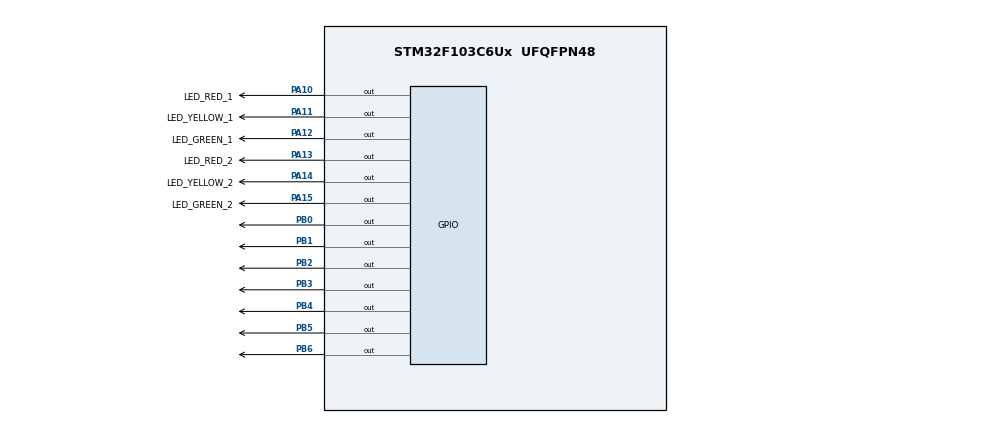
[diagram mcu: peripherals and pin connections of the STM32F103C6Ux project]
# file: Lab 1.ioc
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Mcu.Family=STM32F1
Mcu.Name=STM32F103C6Ux
Mcu.Package=UFQFPN48
NVIC.PriorityGroup=NVIC_PRIORITYGROUP_4
PA10.GPIO_Label=LED_RED_1
PA10.Signal=GPIO_Output
PA11.GPIO_Label=LED_YELLOW_1
PA11.Signal=GPIO_Output
PA12.GPIO_Label=LED_GREEN_1
PA12.Signal=GPIO_Output
PA13.GPIO_Label=LED_RED_2
PA13.Signal=GPIO_Output
PA14.GPIO_Label=LED_YELLOW_2
PA14.Signal=GPIO_Output
PA15.GPIO_Label=LED_GREEN_2
PA15.Signal=GPIO_Output
PB0.Signal=GPIO_Output
PB1.Signal=GPIO_Output
PB2.Signal=GPIO_Output
PB3.Signal=GPIO_Output
PB4.Signal=GPIO_Output
PB5.Signal=GPIO_Output
PB6.Signal=GPIO_Output
ProjectManager.HeapSize=0x200
ProjectManager.StackSize=0x400
ProjectManager.TargetToolchain=STM32CubeIDE
RCC.APB1Freq_Value=8000000
RCC.APB2Freq_Value=8000000
board=custom

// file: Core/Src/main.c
/* USER CODE BEGIN Header */
/**
  ******************************************************************************
  * @file           : main.c
  * @brief          : Main program body
  ******************************************************************************
  * @attention
  *
  * Copyright (c) 2022 STMicroelectronics.
  * All rights reserved.
  *
  * This software is licensed under terms that can be found in the LICENSE file
  * in the root directory of this software component.
  * If no LICENSE file comes with this software, it is provided AS-IS.
  *
  ******************************************************************************
  */
/* USER CODE END Header */
#include "main.h"

void SystemClock_Config(void);
static void MX_GPIO_Init(void);
/* USER CODE BEGIN PFP */
void display_only_LED(int num);
/* USER CODE END PFP */

int main(void)
{

  /* MCU Configuration--------------------------------------------------------*/

  /* Reset of all peripherals, Initializes the Flash interface and the Systick. */
  HAL_Init();

  /* Configure the system clock */
  SystemClock_Config();

  /* Initialize all configured peripherals */
  MX_GPIO_Init();
  /* USER CODE BEGIN 2 */

  int counter = 0;
  /* USER CODE END 2 */

  /* Infinite loop */
  while (1)
  {

    /* USER CODE BEGIN 3 */
	  if( counter >= 12) counter = 0;
	  display_only_LED ( counter ++) ;
	  HAL_Delay (1000) ;
  }
  /* USER CODE END 3 */
}

void SystemClock_Config(void)
{
  RCC_OscInitTypeDef RCC_OscInitStruct = {0};
  RCC_ClkInitTypeDef RCC_ClkInitStruct = {0};

  /** Initializes the RCC Oscillators according to the specified parameters
  * in the RCC_OscInitTypeDef structure.
  */
  RCC_OscInitStruct.OscillatorType = RCC_OSCILLATORTYPE_HSI;
  RCC_OscInitStruct.HSIState = RCC_HSI_ON;
  RCC_OscInitStruct.HSICalibrationValue = RCC_HSICALIBRATION_DEFAULT;
  RCC_OscInitStruct.PLL.PLLState = RCC_PLL_NONE;
  if (HAL_RCC_OscConfig(&RCC_OscInitStruct) != HAL_OK)
  {
    Error_Handler();
  }

  /** Initializes the CPU, AHB and APB buses clocks
  */
  RCC_ClkInitStruct.ClockType = RCC_CLOCKTYPE_HCLK|RCC_CLOCKTYPE_SYSCLK
                              |RCC_CLOCKTYPE_PCLK1|RCC_CLOCKTYPE_PCLK2;
  RCC_ClkInitStruct.SYSCLKSource = RCC_SYSCLKSOURCE_HSI;
  RCC_ClkInitStruct.AHBCLKDivider = RCC_SYSCLK_DIV1;
  RCC_ClkInitStruct.APB1CLKDivider = RCC_HCLK_DIV1;
  RCC_ClkInitStruct.APB2CLKDivider = RCC_HCLK_DIV1;

  if (HAL_RCC_ClockConfig(&RCC_ClkInitStruct, FLASH_LATENCY_0) != HAL_OK)
  {
    Error_Handler();
  }
}

static void MX_GPIO_Init(void)
{
  GPIO_InitTypeDef GPIO_InitStruct = {0};

  /* GPIO Ports Clock Enable */
  __HAL_RCC_GPIOA_CLK_ENABLE();

  /*Configure GPIO pin Output Level */
  HAL_GPIO_WritePin(GPIOA, GPIO_PIN_4|GPIO_PIN_5|GPIO_PIN_6|GPIO_PIN_7
                          |GPIO_PIN_8|GPIO_PIN_9|GPIO_PIN_10|GPIO_PIN_11
                          |GPIO_PIN_12|GPIO_PIN_13|GPIO_PIN_14|GPIO_PIN_15, GPIO_PIN_RESET);

  /*Configure GPIO pins : PA4 PA5 PA6 PA7
                           PA8 PA9 PA10 PA11
                           PA12 PA13 PA14 PA15 */
  GPIO_InitStruct.Pin = GPIO_PIN_4|GPIO_PIN_5|GPIO_PIN_6|GPIO_PIN_7
                          |GPIO_PIN_8|GPIO_PIN_9|GPIO_PIN_10|GPIO_PIN_11
                          |GPIO_PIN_12|GPIO_PIN_13|GPIO_PIN_14|GPIO_PIN_15;
  GPIO_InitStruct.Mode = GPIO_MODE_OUTPUT_PP;
  GPIO_InitStruct.Pull = GPIO_NOPULL;
  GPIO_InitStruct.Speed = GPIO_SPEED_FREQ_LOW;
  HAL_GPIO_Init(GPIOA, &GPIO_InitStruct);

}

/* USER CODE BEGIN 4 */
void display_only_LED(int num)
{
	/*
	* Test a LED is on, other LEDs are off
	*/
	switch(num){
	case 0:
		HAL_GPIO_WritePin(GPIOA, GPIO_PIN_4, RESET);
		HAL_GPIO_WritePin(GPIOA, GPIO_PIN_All ^ GPIO_PIN_4, SET);
		break;
	case 1:
		HAL_GPIO_WritePin(GPIOA, GPIO_PIN_5, RESET);
		HAL_GPIO_WritePin(GPIOA, GPIO_PIN_All ^ GPIO_PIN_5, SET);
		break;
	case 2:
		HAL_GPIO_WritePin(GPIOA, GPIO_PIN_6, RESET);
		HAL_GPIO_WritePin(GPIOA, GPIO_PIN_All ^ GPIO_PIN_6, SET);
		break;
	case 3:
		HAL_GPIO_WritePin(GPIOA, GPIO_PIN_7, RESET);
		HAL_GPIO_WritePin(GPIOA, GPIO_PIN_All ^ GPIO_PIN_7, SET);
		break;
	case 4:
		HAL_GPIO_WritePin(GPIOA, GPIO_PIN_8, RESET);
		HAL_GPIO_WritePin(GPIOA, GPIO_PIN_All ^ GPIO_PIN_8, SET);
		break;
	case 5:
		HAL_GPIO_WritePin(GPIOA, GPIO_PIN_9, RESET);
		HAL_GPIO_WritePin(GPIOA, GPIO_PIN_All ^ GPIO_PIN_9, SET);
		break;
	case 6:
		HAL_GPIO_WritePin(GPIOA, GPIO_PIN_10, RESET);
		HAL_GPIO_WritePin(GPIOA, GPIO_PIN_All ^ GPIO_PIN_10, SET);
		break;
	case 7:
		HAL_GPIO_WritePin(GPIOA, GPIO_PIN_11, RESET);
		HAL_GPIO_WritePin(GPIOA, GPIO_PIN_All ^ GPIO_PIN_11, SET);
		break;
	case 8:
		HAL_GPIO_WritePin(GPIOA, GPIO_PIN_12, RESET);
		HAL_GPIO_WritePin(GPIOA, GPIO_PIN_All ^ GPIO_PIN_12, SET);
		break;
	case 9:
		HAL_GPIO_WritePin(GPIOA, GPIO_PIN_13, RESET);
		HAL_GPIO_WritePin(GPIOA, GPIO_PIN_All ^ GPIO_PIN_13, SET);
		break;
	case 10:
		HAL_GPIO_WritePin(GPIOA, GPIO_PIN_14, RESET);
		HAL_GPIO_WritePin(GPIOA, GPIO_PIN_All ^ GPIO_PIN_14, SET);
		break;
	case 11:
		HAL_GPIO_WritePin(GPIOA, GPIO_PIN_15, RESET);
		HAL_GPIO_WritePin(GPIOA, GPIO_PIN_All ^ GPIO_PIN_15, SET);
		break;
	}
}
/* USER CODE END 4 */

void Error_Handler(void)
{
  __disable_irq();
  while (1)
  {
  }
}
